VERSION 5.7 ;
  NOWIREEXTENSIONATPIN ON ;
  DIVIDERCHAR "/" ;
  BUSBITCHARS "[]" ;
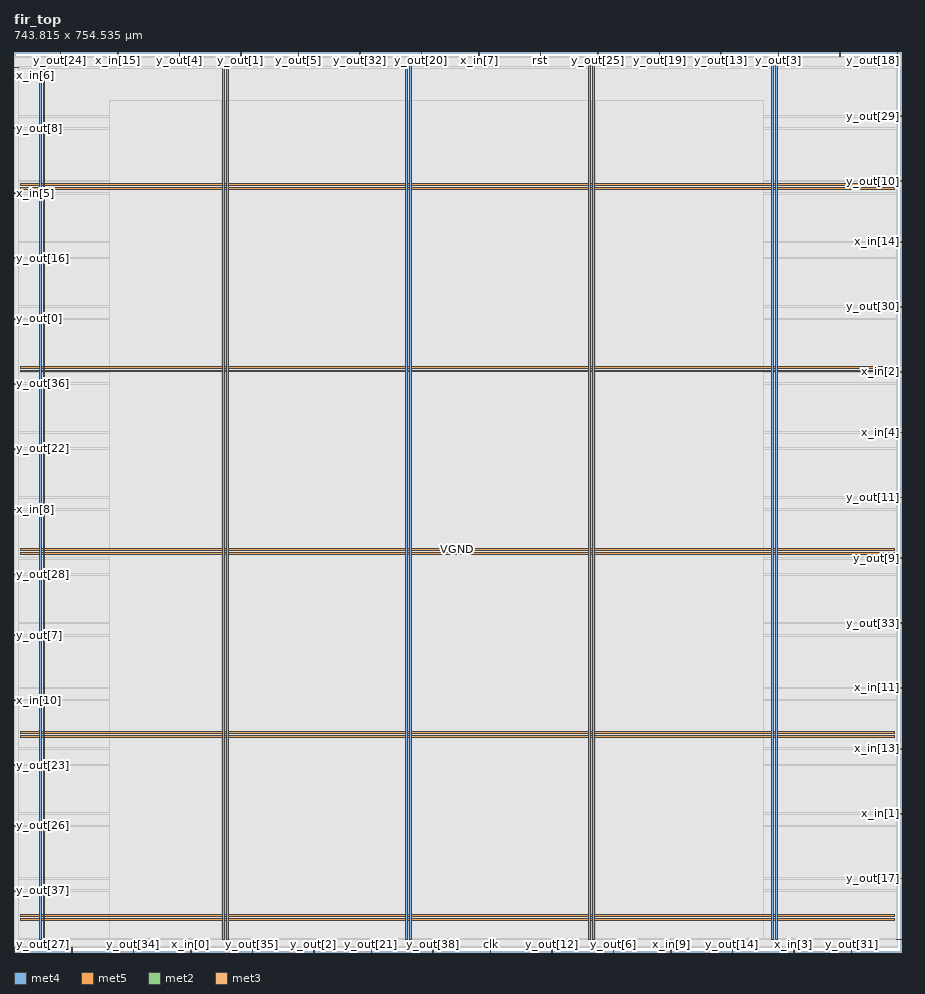
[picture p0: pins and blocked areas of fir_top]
MACRO fir_top
  CLASS BLOCK ;
  FOREIGN fir_top ;
  ORIGIN 0.000 0.000 ;
  SIZE 743.815 BY 754.535 ;
  PIN VGND
    DIRECTION INOUT ;
    USE GROUND ;
    PORT
      LAYER met4 ;
        RECT 24.340 10.640 25.940 742.800 ;
    END
    PORT
      LAYER met4 ;
        RECT 177.940 10.640 179.540 742.800 ;
    END
    PORT
      LAYER met4 ;
        RECT 331.540 10.640 333.140 742.800 ;
    END
    PORT
      LAYER met4 ;
        RECT 485.140 10.640 486.740 742.800 ;
    END
    PORT
      LAYER met4 ;
        RECT 638.740 10.640 640.340 742.800 ;
    END
    PORT
      LAYER met5 ;
        RECT 5.280 30.030 738.080 31.630 ;
    END
    PORT
      LAYER met5 ;
        RECT 5.280 183.210 738.080 184.810 ;
    END
    PORT
      LAYER met5 ;
        RECT 5.280 336.390 738.080 337.990 ;
    END
    PORT
      LAYER met5 ;
        RECT 5.280 489.570 738.080 491.170 ;
    END
    PORT
      LAYER met5 ;
        RECT 5.280 642.750 738.080 644.350 ;
    END
  END VGND
  PIN VPWR
    DIRECTION INOUT ;
    USE POWER ;
    PORT
      LAYER met4 ;
        RECT 21.040 10.640 22.640 742.800 ;
    END
    PORT
      LAYER met4 ;
        RECT 174.640 10.640 176.240 742.800 ;
    END
    PORT
      LAYER met4 ;
        RECT 328.240 10.640 329.840 742.800 ;
    END
    PORT
      LAYER met4 ;
        RECT 481.840 10.640 483.440 742.800 ;
    END
    PORT
      LAYER met4 ;
        RECT 635.440 10.640 637.040 742.800 ;
    END
    PORT
      LAYER met5 ;
        RECT 5.280 26.730 738.080 28.330 ;
    END
    PORT
      LAYER met5 ;
        RECT 5.280 179.910 738.080 181.510 ;
    END
    PORT
      LAYER met5 ;
        RECT 5.280 333.090 738.080 334.690 ;
    END
    PORT
      LAYER met5 ;
        RECT 5.280 486.270 738.080 487.870 ;
    END
    PORT
      LAYER met5 ;
        RECT 5.280 639.450 738.080 641.050 ;
    END
  END VPWR
  PIN clk
    DIRECTION INPUT ;
    USE SIGNAL ;
    ANTENNAGATEAREA 1.286700 ;
    ANTENNADIFFAREA 0.434700 ;
    PORT
      LAYER met2 ;
        RECT 399.370 0.000 399.650 4.000 ;
    END
  END clk
  PIN rst
    DIRECTION INPUT ;
    USE SIGNAL ;
    ANTENNAGATEAREA 0.126000 ;
    PORT
      LAYER met2 ;
        RECT 441.230 750.535 441.510 754.535 ;
    END
  END rst
  PIN x_in[0]
    DIRECTION INPUT ;
    USE SIGNAL ;
    ANTENNAGATEAREA 0.126000 ;
    PORT
      LAYER met2 ;
        RECT 148.210 0.000 148.490 4.000 ;
    END
  END x_in[0]
  PIN x_in[10]
    DIRECTION INPUT ;
    USE SIGNAL ;
    ANTENNAGATEAREA 0.126000 ;
    PORT
      LAYER met3 ;
        RECT 0.000 210.840 4.000 211.440 ;
    END
  END x_in[10]
  PIN x_in[11]
    DIRECTION INPUT ;
    USE SIGNAL ;
    ANTENNAGATEAREA 0.126000 ;
    PORT
      LAYER met3 ;
        RECT 739.815 221.040 743.815 221.640 ;
    END
  END x_in[11]
  PIN x_in[12]
    DIRECTION INPUT ;
    USE SIGNAL ;
    ANTENNAGATEAREA 0.126000 ;
    PORT
      LAYER met2 ;
        RECT 48.390 0.000 48.670 4.000 ;
    END
  END x_in[12]
  PIN x_in[13]
    DIRECTION INPUT ;
    USE SIGNAL ;
    ANTENNAGATEAREA 0.126000 ;
    PORT
      LAYER met3 ;
        RECT 739.815 170.040 743.815 170.640 ;
    END
  END x_in[13]
  PIN x_in[14]
    DIRECTION INPUT ;
    USE SIGNAL ;
    ANTENNAGATEAREA 0.126000 ;
    PORT
      LAYER met3 ;
        RECT 739.815 595.040 743.815 595.640 ;
    END
  END x_in[14]
  PIN x_in[15]
    DIRECTION INPUT ;
    USE SIGNAL ;
    ANTENNAGATEAREA 0.126000 ;
    PORT
      LAYER met2 ;
        RECT 87.030 750.535 87.310 754.535 ;
    END
  END x_in[15]
  PIN x_in[1]
    DIRECTION INPUT ;
    USE SIGNAL ;
    ANTENNAGATEAREA 0.126000 ;
    PORT
      LAYER met3 ;
        RECT 739.815 115.640 743.815 116.240 ;
    END
  END x_in[1]
  PIN x_in[2]
    DIRECTION INPUT ;
    USE SIGNAL ;
    ANTENNAGATEAREA 0.126000 ;
    PORT
      LAYER met3 ;
        RECT 739.815 486.240 743.815 486.840 ;
    END
  END x_in[2]
  PIN x_in[3]
    DIRECTION INPUT ;
    USE SIGNAL ;
    ANTENNAGATEAREA 0.126000 ;
    PORT
      LAYER met2 ;
        RECT 653.750 0.000 654.030 4.000 ;
    END
  END x_in[3]
  PIN x_in[4]
    DIRECTION INPUT ;
    USE SIGNAL ;
    ANTENNAGATEAREA 0.126000 ;
    PORT
      LAYER met3 ;
        RECT 739.815 435.240 743.815 435.840 ;
    END
  END x_in[4]
  PIN x_in[5]
    DIRECTION INPUT ;
    USE SIGNAL ;
    ANTENNAGATEAREA 0.126000 ;
    PORT
      LAYER met3 ;
        RECT 0.000 635.840 4.000 636.440 ;
    END
  END x_in[5]
  PIN x_in[6]
    DIRECTION INPUT ;
    USE SIGNAL ;
    ANTENNAGATEAREA 0.126000 ;
    PORT
      LAYER met3 ;
        RECT 0.000 741.240 4.000 741.840 ;
    END
  END x_in[6]
  PIN x_in[7]
    DIRECTION INPUT ;
    USE SIGNAL ;
    ANTENNAGATEAREA 0.126000 ;
    PORT
      LAYER met2 ;
        RECT 389.710 750.535 389.990 754.535 ;
    END
  END x_in[7]
  PIN x_in[8]
    DIRECTION INPUT ;
    USE SIGNAL ;
    ANTENNAGATEAREA 0.126000 ;
    PORT
      LAYER met3 ;
        RECT 0.000 370.640 4.000 371.240 ;
    END
  END x_in[8]
  PIN x_in[9]
    DIRECTION INPUT ;
    USE SIGNAL ;
    ANTENNAGATEAREA 0.126000 ;
    PORT
      LAYER met2 ;
        RECT 550.710 0.000 550.990 4.000 ;
    END
  END x_in[9]
  PIN y_out[0]
    DIRECTION OUTPUT TRISTATE ;
    USE SIGNAL ;
    ANTENNADIFFAREA 0.795200 ;
    PORT
      LAYER met3 ;
        RECT 0.000 530.440 4.000 531.040 ;
    END
  END y_out[0]
  PIN y_out[10]
    DIRECTION OUTPUT TRISTATE ;
    USE SIGNAL ;
    ANTENNADIFFAREA 0.445500 ;
    PORT
      LAYER met3 ;
        RECT 739.815 646.040 743.815 646.640 ;
    END
  END y_out[10]
  PIN y_out[11]
    DIRECTION OUTPUT TRISTATE ;
    USE SIGNAL ;
    ANTENNADIFFAREA 0.445500 ;
    PORT
      LAYER met3 ;
        RECT 739.815 380.840 743.815 381.440 ;
    END
  END y_out[11]
  PIN y_out[12]
    DIRECTION OUTPUT TRISTATE ;
    USE SIGNAL ;
    ANTENNADIFFAREA 0.795200 ;
    PORT
      LAYER met2 ;
        RECT 450.890 0.000 451.170 4.000 ;
    END
  END y_out[12]
  PIN y_out[13]
    DIRECTION OUTPUT TRISTATE ;
    USE SIGNAL ;
    ANTENNADIFFAREA 0.795200 ;
    PORT
      LAYER met2 ;
        RECT 592.570 750.535 592.850 754.535 ;
    END
  END y_out[13]
  PIN y_out[14]
    DIRECTION OUTPUT TRISTATE ;
    USE SIGNAL ;
    ANTENNADIFFAREA 0.795200 ;
    PORT
      LAYER met2 ;
        RECT 602.230 0.000 602.510 4.000 ;
    END
  END y_out[14]
  PIN y_out[15]
    DIRECTION OUTPUT TRISTATE ;
    USE SIGNAL ;
    ANTENNADIFFAREA 0.445500 ;
    PORT
      LAYER met3 ;
        RECT 739.815 10.240 743.815 10.840 ;
    END
  END y_out[15]
  PIN y_out[16]
    DIRECTION OUTPUT TRISTATE ;
    USE SIGNAL ;
    ANTENNADIFFAREA 0.795200 ;
    PORT
      LAYER met3 ;
        RECT 0.000 581.440 4.000 582.040 ;
    END
  END y_out[16]
  PIN y_out[17]
    DIRECTION OUTPUT TRISTATE ;
    USE SIGNAL ;
    ANTENNADIFFAREA 0.795200 ;
    PORT
      LAYER met3 ;
        RECT 739.815 61.240 743.815 61.840 ;
    END
  END y_out[17]
  PIN y_out[18]
    DIRECTION OUTPUT TRISTATE ;
    USE SIGNAL ;
    ANTENNADIFFAREA 0.795200 ;
    PORT
      LAYER met2 ;
        RECT 740.690 750.535 740.970 754.535 ;
    END
  END y_out[18]
  PIN y_out[19]
    DIRECTION OUTPUT TRISTATE ;
    USE SIGNAL ;
    ANTENNADIFFAREA 0.795200 ;
    PORT
      LAYER met2 ;
        RECT 541.050 750.535 541.330 754.535 ;
    END
  END y_out[19]
  PIN y_out[1]
    DIRECTION OUTPUT TRISTATE ;
    USE SIGNAL ;
    ANTENNADIFFAREA 0.795200 ;
    PORT
      LAYER met2 ;
        RECT 190.070 750.535 190.350 754.535 ;
    END
  END y_out[1]
  PIN y_out[20]
    DIRECTION OUTPUT TRISTATE ;
    USE SIGNAL ;
    ANTENNADIFFAREA 0.445500 ;
    PORT
      LAYER met2 ;
        RECT 341.410 750.535 341.690 754.535 ;
    END
  END y_out[20]
  PIN y_out[21]
    DIRECTION OUTPUT TRISTATE ;
    USE SIGNAL ;
    ANTENNADIFFAREA 0.795200 ;
    PORT
      LAYER met2 ;
        RECT 299.550 0.000 299.830 4.000 ;
    END
  END y_out[21]
  PIN y_out[22]
    DIRECTION OUTPUT TRISTATE ;
    USE SIGNAL ;
    ANTENNADIFFAREA 0.795200 ;
    PORT
      LAYER met3 ;
        RECT 0.000 421.640 4.000 422.240 ;
    END
  END y_out[22]
  PIN y_out[23]
    DIRECTION OUTPUT TRISTATE ;
    USE SIGNAL ;
    ANTENNADIFFAREA 0.795200 ;
    PORT
      LAYER met3 ;
        RECT 0.000 156.440 4.000 157.040 ;
    END
  END y_out[23]
  PIN y_out[24]
    DIRECTION OUTPUT TRISTATE ;
    USE SIGNAL ;
    ANTENNADIFFAREA 0.795200 ;
    PORT
      LAYER met2 ;
        RECT 38.730 750.535 39.010 754.535 ;
    END
  END y_out[24]
  PIN y_out[25]
    DIRECTION OUTPUT TRISTATE ;
    USE SIGNAL ;
    ANTENNADIFFAREA 0.795200 ;
    PORT
      LAYER met2 ;
        RECT 489.530 750.535 489.810 754.535 ;
    END
  END y_out[25]
  PIN y_out[26]
    DIRECTION OUTPUT TRISTATE ;
    USE SIGNAL ;
    ANTENNADIFFAREA 0.795200 ;
    PORT
      LAYER met3 ;
        RECT 0.000 105.440 4.000 106.040 ;
    END
  END y_out[26]
  PIN y_out[27]
    DIRECTION OUTPUT TRISTATE ;
    USE SIGNAL ;
    ANTENNADIFFAREA 0.795200 ;
    PORT
      LAYER met2 ;
        RECT 0.090 0.000 0.370 4.000 ;
    END
  END y_out[27]
  PIN y_out[28]
    DIRECTION OUTPUT TRISTATE ;
    USE SIGNAL ;
    ANTENNADIFFAREA 0.795200 ;
    PORT
      LAYER met3 ;
        RECT 0.000 316.240 4.000 316.840 ;
    END
  END y_out[28]
  PIN y_out[29]
    DIRECTION OUTPUT TRISTATE ;
    USE SIGNAL ;
    ANTENNADIFFAREA 0.445500 ;
    PORT
      LAYER met3 ;
        RECT 739.815 700.440 743.815 701.040 ;
    END
  END y_out[29]
  PIN y_out[2]
    DIRECTION OUTPUT TRISTATE ;
    USE SIGNAL ;
    ANTENNADIFFAREA 0.795200 ;
    PORT
      LAYER met2 ;
        RECT 251.250 0.000 251.530 4.000 ;
    END
  END y_out[2]
  PIN y_out[30]
    DIRECTION OUTPUT TRISTATE ;
    USE SIGNAL ;
    ANTENNADIFFAREA 0.445500 ;
    PORT
      LAYER met3 ;
        RECT 739.815 540.640 743.815 541.240 ;
    END
  END y_out[30]
  PIN y_out[31]
    DIRECTION OUTPUT TRISTATE ;
    USE SIGNAL ;
    ANTENNADIFFAREA 0.795200 ;
    PORT
      LAYER met2 ;
        RECT 702.050 0.000 702.330 4.000 ;
    END
  END y_out[31]
  PIN y_out[32]
    DIRECTION OUTPUT TRISTATE ;
    USE SIGNAL ;
    ANTENNADIFFAREA 0.795200 ;
    PORT
      LAYER met2 ;
        RECT 289.890 750.535 290.170 754.535 ;
    END
  END y_out[32]
  PIN y_out[33]
    DIRECTION OUTPUT TRISTATE ;
    USE SIGNAL ;
    ANTENNADIFFAREA 0.795200 ;
    PORT
      LAYER met3 ;
        RECT 739.815 275.440 743.815 276.040 ;
    END
  END y_out[33]
  PIN y_out[34]
    DIRECTION OUTPUT TRISTATE ;
    USE SIGNAL ;
    ANTENNADIFFAREA 0.795200 ;
    PORT
      LAYER met2 ;
        RECT 99.910 0.000 100.190 4.000 ;
    END
  END y_out[34]
  PIN y_out[35]
    DIRECTION OUTPUT TRISTATE ;
    USE SIGNAL ;
    ANTENNADIFFAREA 0.795200 ;
    PORT
      LAYER met2 ;
        RECT 199.730 0.000 200.010 4.000 ;
    END
  END y_out[35]
  PIN y_out[36]
    DIRECTION OUTPUT TRISTATE ;
    USE SIGNAL ;
    ANTENNADIFFAREA 0.795200 ;
    PORT
      LAYER met3 ;
        RECT 0.000 476.040 4.000 476.640 ;
    END
  END y_out[36]
  PIN y_out[37]
    DIRECTION OUTPUT TRISTATE ;
    USE SIGNAL ;
    ANTENNADIFFAREA 0.795200 ;
    PORT
      LAYER met3 ;
        RECT 0.000 51.040 4.000 51.640 ;
    END
  END y_out[37]
  PIN y_out[38]
    DIRECTION OUTPUT TRISTATE ;
    USE SIGNAL ;
    ANTENNADIFFAREA 0.795200 ;
    PORT
      LAYER met2 ;
        RECT 351.070 0.000 351.350 4.000 ;
    END
  END y_out[38]
  PIN y_out[39]
    DIRECTION OUTPUT TRISTATE ;
    USE SIGNAL ;
    ANTENNADIFFAREA 0.795200 ;
    PORT
      LAYER met2 ;
        RECT 692.390 750.535 692.670 754.535 ;
    END
  END y_out[39]
  PIN y_out[3]
    DIRECTION OUTPUT TRISTATE ;
    USE SIGNAL ;
    ANTENNADIFFAREA 0.795200 ;
    PORT
      LAYER met2 ;
        RECT 640.870 750.535 641.150 754.535 ;
    END
  END y_out[3]
  PIN y_out[4]
    DIRECTION OUTPUT TRISTATE ;
    USE SIGNAL ;
    ANTENNADIFFAREA 0.795200 ;
    PORT
      LAYER met2 ;
        RECT 138.550 750.535 138.830 754.535 ;
    END
  END y_out[4]
  PIN y_out[5]
    DIRECTION OUTPUT TRISTATE ;
    USE SIGNAL ;
    ANTENNADIFFAREA 0.795200 ;
    PORT
      LAYER met2 ;
        RECT 238.370 750.535 238.650 754.535 ;
    END
  END y_out[5]
  PIN y_out[6]
    DIRECTION OUTPUT TRISTATE ;
    USE SIGNAL ;
    ANTENNADIFFAREA 0.795200 ;
    PORT
      LAYER met2 ;
        RECT 502.410 0.000 502.690 4.000 ;
    END
  END y_out[6]
  PIN y_out[7]
    DIRECTION OUTPUT TRISTATE ;
    USE SIGNAL ;
    ANTENNADIFFAREA 0.795200 ;
    PORT
      LAYER met3 ;
        RECT 0.000 265.240 4.000 265.840 ;
    END
  END y_out[7]
  PIN y_out[8]
    DIRECTION OUTPUT TRISTATE ;
    USE SIGNAL ;
    ANTENNADIFFAREA 0.795200 ;
    PORT
      LAYER met3 ;
        RECT 0.000 690.240 4.000 690.840 ;
    END
  END y_out[8]
  PIN y_out[9]
    DIRECTION OUTPUT TRISTATE ;
    USE SIGNAL ;
    ANTENNADIFFAREA 0.445500 ;
    PORT
      LAYER met3 ;
        RECT 739.815 329.840 743.815 330.440 ;
    END
  END y_out[9]
  OBS
      LAYER li1 ;
        RECT 5.520 10.795 737.840 742.645 ;
      LAYER met1 ;
        RECT 0.070 10.640 740.990 742.800 ;
      LAYER met2 ;
        RECT 0.100 750.255 38.450 751.130 ;
        RECT 39.290 750.255 86.750 751.130 ;
        RECT 87.590 750.255 138.270 751.130 ;
        RECT 139.110 750.255 189.790 751.130 ;
        RECT 190.630 750.255 238.090 751.130 ;
        RECT 238.930 750.255 289.610 751.130 ;
        RECT 290.450 750.255 341.130 751.130 ;
        RECT 341.970 750.255 389.430 751.130 ;
        RECT 390.270 750.255 440.950 751.130 ;
        RECT 441.790 750.255 489.250 751.130 ;
        RECT 490.090 750.255 540.770 751.130 ;
        RECT 541.610 750.255 592.290 751.130 ;
        RECT 593.130 750.255 640.590 751.130 ;
        RECT 641.430 750.255 692.110 751.130 ;
        RECT 692.950 750.255 740.410 751.130 ;
        RECT 0.100 4.280 740.960 750.255 ;
        RECT 0.650 4.000 48.110 4.280 ;
        RECT 48.950 4.000 99.630 4.280 ;
        RECT 100.470 4.000 147.930 4.280 ;
        RECT 148.770 4.000 199.450 4.280 ;
        RECT 200.290 4.000 250.970 4.280 ;
        RECT 251.810 4.000 299.270 4.280 ;
        RECT 300.110 4.000 350.790 4.280 ;
        RECT 351.630 4.000 399.090 4.280 ;
        RECT 399.930 4.000 450.610 4.280 ;
        RECT 451.450 4.000 502.130 4.280 ;
        RECT 502.970 4.000 550.430 4.280 ;
        RECT 551.270 4.000 601.950 4.280 ;
        RECT 602.790 4.000 653.470 4.280 ;
        RECT 654.310 4.000 701.770 4.280 ;
        RECT 702.610 4.000 740.960 4.280 ;
      LAYER met3 ;
        RECT 3.990 742.240 739.815 742.725 ;
        RECT 4.400 740.840 739.815 742.240 ;
        RECT 3.990 701.440 739.815 740.840 ;
        RECT 3.990 700.040 739.415 701.440 ;
        RECT 3.990 691.240 739.815 700.040 ;
        RECT 4.400 689.840 739.815 691.240 ;
        RECT 3.990 647.040 739.815 689.840 ;
        RECT 3.990 645.640 739.415 647.040 ;
        RECT 3.990 636.840 739.815 645.640 ;
        RECT 4.400 635.440 739.815 636.840 ;
        RECT 3.990 596.040 739.815 635.440 ;
        RECT 3.990 594.640 739.415 596.040 ;
        RECT 3.990 582.440 739.815 594.640 ;
        RECT 4.400 581.040 739.815 582.440 ;
        RECT 3.990 541.640 739.815 581.040 ;
        RECT 3.990 540.240 739.415 541.640 ;
        RECT 3.990 531.440 739.815 540.240 ;
        RECT 4.400 530.040 739.815 531.440 ;
        RECT 3.990 487.240 739.815 530.040 ;
        RECT 3.990 485.840 739.415 487.240 ;
        RECT 3.990 477.040 739.815 485.840 ;
        RECT 4.400 475.640 739.815 477.040 ;
        RECT 3.990 436.240 739.815 475.640 ;
        RECT 3.990 434.840 739.415 436.240 ;
        RECT 3.990 422.640 739.815 434.840 ;
        RECT 4.400 421.240 739.815 422.640 ;
        RECT 3.990 381.840 739.815 421.240 ;
        RECT 3.990 380.440 739.415 381.840 ;
        RECT 3.990 371.640 739.815 380.440 ;
        RECT 4.400 370.240 739.815 371.640 ;
        RECT 3.990 330.840 739.815 370.240 ;
        RECT 3.990 329.440 739.415 330.840 ;
        RECT 3.990 317.240 739.815 329.440 ;
        RECT 4.400 315.840 739.815 317.240 ;
        RECT 3.990 276.440 739.815 315.840 ;
        RECT 3.990 275.040 739.415 276.440 ;
        RECT 3.990 266.240 739.815 275.040 ;
        RECT 4.400 264.840 739.815 266.240 ;
        RECT 3.990 222.040 739.815 264.840 ;
        RECT 3.990 220.640 739.415 222.040 ;
        RECT 3.990 211.840 739.815 220.640 ;
        RECT 4.400 210.440 739.815 211.840 ;
        RECT 3.990 171.040 739.815 210.440 ;
        RECT 3.990 169.640 739.415 171.040 ;
        RECT 3.990 157.440 739.815 169.640 ;
        RECT 4.400 156.040 739.815 157.440 ;
        RECT 3.990 116.640 739.815 156.040 ;
        RECT 3.990 115.240 739.415 116.640 ;
        RECT 3.990 106.440 739.815 115.240 ;
        RECT 4.400 105.040 739.815 106.440 ;
        RECT 3.990 62.240 739.815 105.040 ;
        RECT 3.990 60.840 739.415 62.240 ;
        RECT 3.990 52.040 739.815 60.840 ;
        RECT 4.400 50.640 739.815 52.040 ;
        RECT 3.990 11.240 739.815 50.640 ;
        RECT 3.990 10.375 739.415 11.240 ;
      LAYER met4 ;
        RECT 80.335 11.735 174.240 713.825 ;
        RECT 176.640 11.735 177.540 713.825 ;
        RECT 179.940 11.735 327.840 713.825 ;
        RECT 330.240 11.735 331.140 713.825 ;
        RECT 333.540 11.735 481.440 713.825 ;
        RECT 483.840 11.735 484.740 713.825 ;
        RECT 487.140 11.735 628.065 713.825 ;
  END
END fir_top
END LIBRARY

